VERSION 5.8 ;
BUSBITCHARS "[]" ;
DIVIDERCHAR "/" ;

VIA TPL1_C_0
  VIARULE TPL1_C ;
  CUTSIZE 0.17 0.17 ;
  LAYERS tap licon1 li1 ;
  CUTSPACING 0.17 0.17 ;
  ENCLOSURE 0.12 0.12 0.08 0.08 ;
  ROWCOL 1 1 ;
END TPL1_C_0

VIA TPL1_C_1
  VIARULE TPL1_C ;
  CUTSIZE 0.17 0.17 ;
  LAYERS tap licon1 li1 ;
  CUTSPACING 0.17 0.17 ;
  ENCLOSURE 0.12 0.12 0.08 0.08 ;
  ROWCOL 1 26 ;
END TPL1_C_1

VIA TPL1_C_2
  VIARULE TPL1_C ;
  CUTSIZE 0.17 0.17 ;
  LAYERS tap licon1 li1 ;
  CUTSPACING 0.17 0.17 ;
  ENCLOSURE 0.12 0.12 0.08 0.08 ;
  ROWCOL 1 24 ;
END TPL1_C_2

VIA PYL1_C_3
  VIARULE PYL1_C ;
  CUTSIZE 0.17 0.17 ;
  LAYERS poly licon1 li1 ;
  CUTSPACING 0.17 0.17 ;
  ENCLOSURE 0.08 0.08 0.08 0.08 ;
  ROWCOL 1 1 ;
END PYL1_C_3

VIA PYL1_C_4
  VIARULE PYL1_C ;
  CUTSIZE 0.17 0.17 ;
  LAYERS poly licon1 li1 ;
  CUTSPACING 0.17 0.17 ;
  ENCLOSURE 0.08 0.08 0.08 0.08 ;
  ROWCOL 1 6 ;
END PYL1_C_4

VIA PYL1_C_5
  VIARULE PYL1_C ;
  CUTSIZE 0.17 0.17 ;
  LAYERS poly licon1 li1 ;
  CUTSPACING 0.17 0.17 ;
  ENCLOSURE 0.08 0.08 0.08 0.08 ;
  ROWCOL 1 2 ;
END PYL1_C_5

VIA PYL1_C_6
  VIARULE PYL1_C ;
  CUTSIZE 0.17 0.17 ;
  LAYERS poly licon1 li1 ;
  CUTSPACING 0.17 0.17 ;
  ENCLOSURE 0.08 0.08 0.08 0.08 ;
  ROWCOL 1 22 ;
END PYL1_C_6

VIA PYL1_C_7
  VIARULE PYL1_C ;
  CUTSIZE 0.17 0.17 ;
  LAYERS poly licon1 li1 ;
  CUTSPACING 0.17 0.17 ;
  ENCLOSURE 0.08 0.08 0.08 0.08 ;
  ROWCOL 1 20 ;
END PYL1_C_7

VIA PYL1_C_8
  VIARULE PYL1_C ;
  CUTSIZE 0.17 0.17 ;
  LAYERS poly licon1 li1 ;
  CUTSPACING 0.17 0.17 ;
  ENCLOSURE 0.08 0.08 0.08 0.08 ;
  ROWCOL 1 23 ;
END PYL1_C_8

VIA PYL1_C_9
  VIARULE PYL1_C ;
  CUTSIZE 0.17 0.17 ;
  LAYERS poly licon1 li1 ;
  CUTSPACING 0.17 0.17 ;
  ENCLOSURE 0.08 0.08 0.08 0.08 ;
  ROWCOL 1 17 ;
END PYL1_C_9

VIA PYL1_C_10
  VIARULE PYL1_C ;
  CUTSIZE 0.17 0.17 ;
  LAYERS poly licon1 li1 ;
  CUTSPACING 0.17 0.17 ;
  ENCLOSURE 0.08 0.08 0.08 0.08 ;
  ROWCOL 1 8 ;
END PYL1_C_10

VIA PYL1_C_11
  VIARULE PYL1_C ;
  CUTSIZE 0.17 0.17 ;
  LAYERS poly licon1 li1 ;
  CUTSPACING 0.17 0.17 ;
  ENCLOSURE 0.08 0.08 0.08 0.08 ;
  ROWCOL 1 10 ;
END PYL1_C_11

VIA PYL1_C_12
  VIARULE PYL1_C ;
  CUTSIZE 0.17 0.17 ;
  LAYERS poly licon1 li1 ;
  CUTSPACING 0.17 0.17 ;
  ENCLOSURE 0.08 0.08 0.08 0.08 ;
  ROWCOL 1 1 ;
END PYL1_C_12

VIA PYL1_C_13
  VIARULE PYL1_C ;
  CUTSIZE 0.17 0.17 ;
  LAYERS poly licon1 li1 ;
  CUTSPACING 0.19 0.19 ;
  ENCLOSURE 0.08 0.08 0.08 0.08 ;
  ROWCOL 1 2 ;
END PYL1_C_13

VIA PYL1_C_14
  VIARULE PYL1_C ;
  CUTSIZE 0.17 0.17 ;
  LAYERS poly licon1 li1 ;
  CUTSPACING 0.17 0.17 ;
  ENCLOSURE 0.08 0.08 0.08 0.08 ;
  ROWCOL 1 14 ;
END PYL1_C_14

VIA PYL1_C_15
  VIARULE PYL1_C ;
  CUTSIZE 0.17 0.17 ;
  LAYERS poly licon1 li1 ;
  CUTSPACING 0.17 0.17 ;
  ENCLOSURE 0.08 0.08 0.08 0.08 ;
  ROWCOL 1 90 ;
END PYL1_C_15

VIA PYL1_C_16
  VIARULE PYL1_C ;
  CUTSIZE 0.17 0.17 ;
  LAYERS poly licon1 li1 ;
  CUTSPACING 0.17 0.17 ;
  ENCLOSURE 0.08 0.08 0.08 0.08 ;
  ROWCOL 1 4 ;
END PYL1_C_16

VIA PYL1_C_17
  VIARULE PYL1_C ;
  CUTSIZE 0.17 0.17 ;
  LAYERS poly licon1 li1 ;
  CUTSPACING 0.17 0.17 ;
  ENCLOSURE 0.08 0.08 0.08 0.08 ;
  ROWCOL 2 1 ;
END PYL1_C_17

VIA L1M1_C_18
  VIARULE L1M1_C ;
  CUTSIZE 0.17 0.17 ;
  LAYERS li1 mcon met1 ;
  CUTSPACING 0.19 0.19 ;
  ENCLOSURE 0 0 0.06 0.06 ;
  ROWCOL 1 1 ;
END L1M1_C_18

VIA L1M1_C_19
  VIARULE L1M1_C ;
  CUTSIZE 0.17 0.17 ;
  LAYERS li1 mcon met1 ;
  CUTSPACING 0.19 0.17 ;
  ENCLOSURE 0 0 0.06 0.06 ;
  ROWCOL 1 2 ;
END L1M1_C_19

VIA L1M1_C_20
  VIARULE L1M1_C ;
  CUTSIZE 0.17 0.17 ;
  LAYERS li1 mcon met1 ;
  CUTSPACING 0.19 0.17 ;
  ENCLOSURE 0 0 0.06 0.06 ;
  ROWCOL 1 18 ;
END L1M1_C_20

VIA L1M1_C_21
  VIARULE L1M1_C ;
  CUTSIZE 0.17 0.17 ;
  LAYERS li1 mcon met1 ;
  CUTSPACING 0.19 0.17 ;
  ENCLOSURE 0 0 0.06 0.06 ;
  ROWCOL 1 9 ;
END L1M1_C_21

VIA L1M1_C_22
  VIARULE L1M1_C ;
  CUTSIZE 0.17 0.17 ;
  LAYERS li1 mcon met1 ;
  CUTSPACING 0.19 0.17 ;
  ENCLOSURE 0 0 0.06 0.06 ;
  ROWCOL 1 3 ;
END L1M1_C_22

VIA L1M1_C_23
  VIARULE L1M1_C ;
  CUTSIZE 0.17 0.17 ;
  LAYERS li1 mcon met1 ;
  CUTSPACING 0.19 0.17 ;
  ENCLOSURE 0 0 0.06 0.06 ;
  ROWCOL 1 10 ;
END L1M1_C_23

VIA L1M1_C_24
  VIARULE L1M1_C ;
  CUTSIZE 0.17 0.17 ;
  LAYERS li1 mcon met1 ;
  CUTSPACING 0.19 0.19 ;
  ENCLOSURE 0 0 0.06 0.06 ;
  ROWCOL 22 1 ;
END L1M1_C_24

VIA L1M1_C_25
  VIARULE L1M1_C ;
  CUTSIZE 0.17 0.17 ;
  LAYERS li1 mcon met1 ;
  CUTSPACING 0.19 0.19 ;
  ENCLOSURE 0 0 0.06 0.06 ;
  ROWCOL 1 20 ;
END L1M1_C_25

VIA L1M1_C_26
  VIARULE L1M1_C ;
  CUTSIZE 0.17 0.17 ;
  LAYERS li1 mcon met1 ;
  CUTSPACING 0.19 0.19 ;
  ENCLOSURE 0 0 0.06 0.06 ;
  ROWCOL 1 8 ;
END L1M1_C_26

VIA L1M1_C_27
  VIARULE L1M1_C ;
  CUTSIZE 0.17 0.17 ;
  LAYERS li1 mcon met1 ;
  CUTSPACING 0.19 0.19 ;
  ENCLOSURE 0 0 0.06 0.06 ;
  ROWCOL 1 3 ;
END L1M1_C_27

VIA L1M1_C_28
  VIARULE L1M1_C ;
  CUTSIZE 0.17 0.17 ;
  LAYERS li1 mcon met1 ;
  CUTSPACING 0.19 0.19 ;
  ENCLOSURE 0 0 0.06 0.06 ;
  ROWCOL 1 12 ;
END L1M1_C_28

VIA L1M1_C_29
  VIARULE L1M1_C ;
  CUTSIZE 0.17 0.17 ;
  LAYERS li1 mcon met1 ;
  CUTSPACING 0.19 0.19 ;
  ENCLOSURE 0 0 0.06 0.06 ;
  ROWCOL 1 4 ;
END L1M1_C_29

VIA L1M1_C_30
  VIARULE L1M1_C ;
  CUTSIZE 0.17 0.17 ;
  LAYERS li1 mcon met1 ;
  CUTSPACING 0.19 0.19 ;
  ENCLOSURE 0 0 0.06 0.06 ;
  ROWCOL 1 85 ;
END L1M1_C_30

VIA L1M1_C_31
  VIARULE L1M1_C ;
  CUTSIZE 0.17 0.17 ;
  LAYERS li1 mcon met1 ;
  CUTSPACING 0.19 0.19 ;
  ENCLOSURE 0 0 0.06 0.06 ;
  ROWCOL 3 1 ;
END L1M1_C_31

VIA L1M1_C_32
  VIARULE L1M1_C ;
  CUTSIZE 0.17 0.17 ;
  LAYERS li1 mcon met1 ;
  CUTSPACING 0.19 0.19 ;
  ENCLOSURE 0 0 0.06 0.06 ;
  ROWCOL 1 2 ;
END L1M1_C_32

VIA L1M1_C_33
  VIARULE L1M1_C ;
  CUTSIZE 0.17 0.17 ;
  LAYERS li1 mcon met1 ;
  CUTSPACING 0.19 0.19 ;
  ENCLOSURE 0 0 0.06 0.06 ;
  ROWCOL 4 1 ;
END L1M1_C_33

VIA L1M1_C_34
  VIARULE L1M1_C ;
  CUTSIZE 0.17 0.17 ;
  LAYERS li1 mcon met1 ;
  CUTSPACING 0.19 0.19 ;
  ENCLOSURE 0 0 0.06 0.06 ;
  ROWCOL 2 2 ;
END L1M1_C_34

VIA L1M1_C_35
  VIARULE L1M1_C ;
  CUTSIZE 0.17 0.17 ;
  LAYERS li1 mcon met1 ;
  CUTSPACING 0.19 0.19 ;
  ENCLOSURE 0 0 0.06 0.06 ;
  ROWCOL 1 1 ;
END L1M1_C_35

VIA L1M1_C_36
  VIARULE L1M1_C ;
  CUTSIZE 0.17 0.17 ;
  LAYERS li1 mcon met1 ;
  CUTSPACING 0.19 0.19 ;
  ENCLOSURE 0 0 0.06 0.06 ;
  ROWCOL 2 1 ;
END L1M1_C_36

VIA L1M1_C_37
  VIARULE L1M1_C ;
  CUTSIZE 0.17 0.17 ;
  LAYERS li1 mcon met1 ;
  CUTSPACING 0.19 0.19 ;
  ENCLOSURE 0 0 0.06 0.06 ;
  ROWCOL 2 18 ;
END L1M1_C_37

VIA L1M1_C_38
  VIARULE L1M1_C ;
  CUTSIZE 0.17 0.17 ;
  LAYERS li1 mcon met1 ;
  CUTSPACING 0.19 0.19 ;
  ENCLOSURE 0 0 0.06 0.06 ;
  ROWCOL 1 7 ;
END L1M1_C_38

VIA M1M2_C_39
  VIARULE M1M2_C ;
  CUTSIZE 0.15 0.15 ;
  LAYERS met1 via met2 ;
  CUTSPACING 0.17 0.17 ;
  ENCLOSURE 0.085 0.085 0.085 0.085 ;
  ROWCOL 1 1 ;
END M1M2_C_39

VIA M1M2_C_40
  VIARULE M1M2_C ;
  CUTSIZE 0.15 0.15 ;
  LAYERS met1 via met2 ;
  CUTSPACING 0.17 0.17 ;
  ENCLOSURE 0.085 0.085 0.085 0.085 ;
  ROWCOL 2 3 ;
END M1M2_C_40

VIA M1M2_C_41
  VIARULE M1M2_C ;
  CUTSIZE 0.15 0.15 ;
  LAYERS met1 via met2 ;
  CUTSPACING 0.21 0.19 ;
  ENCLOSURE 0.085 0.085 0.085 0.085 ;
  ROWCOL 1 7 ;
END M1M2_C_41

VIA M1M2_C_42
  VIARULE M1M2_C ;
  CUTSIZE 0.15 0.15 ;
  LAYERS met1 via met2 ;
  CUTSPACING 0.21 0.19 ;
  ENCLOSURE 0.085 0.085 0.085 0.085 ;
  ROWCOL 1 10 ;
END M1M2_C_42

VIA M1M2_C_43
  VIARULE M1M2_C ;
  CUTSIZE 0.15 0.15 ;
  LAYERS met1 via met2 ;
  CUTSPACING 0.17 0.17 ;
  ENCLOSURE 0.085 0.085 0.085 0.085 ;
  ROWCOL 1 4 ;
END M1M2_C_43

VIA M1M2_C_44
  VIARULE M1M2_C ;
  CUTSIZE 0.15 0.15 ;
  LAYERS met1 via met2 ;
  CUTSPACING 0.17 0.17 ;
  ENCLOSURE 0.085 0.085 0.085 0.085 ;
  ROWCOL 10 1 ;
END M1M2_C_44

VIA M1M2_C_45
  VIARULE M1M2_C ;
  CUTSIZE 0.15 0.15 ;
  LAYERS met1 via met2 ;
  CUTSPACING 0.17 0.17 ;
  ENCLOSURE 0.085 0.085 0.085 0.085 ;
  ROWCOL 5 1 ;
END M1M2_C_45

VIA M1M2_C_46
  VIARULE M1M2_C ;
  CUTSIZE 0.15 0.15 ;
  LAYERS met1 via met2 ;
  CUTSPACING 0.17 0.17 ;
  ENCLOSURE 0.085 0.085 0.085 0.085 ;
  ROWCOL 14 1 ;
END M1M2_C_46

VIA M1M2_C_47
  VIARULE M1M2_C ;
  CUTSIZE 0.15 0.15 ;
  LAYERS met1 via met2 ;
  CUTSPACING 0.17 0.17 ;
  ENCLOSURE 0.085 0.085 0.085 0.085 ;
  ROWCOL 16 8 ;
END M1M2_C_47

VIA M1M2_C_48
  VIARULE M1M2_C ;
  CUTSIZE 0.15 0.15 ;
  LAYERS met1 via met2 ;
  CUTSPACING 0.17 0.17 ;
  ENCLOSURE 0.085 0.085 0.085 0.085 ;
  ROWCOL 3 5 ;
END M1M2_C_48

VIA M1M2_C_49
  VIARULE M1M2_C ;
  CUTSIZE 0.15 0.15 ;
  LAYERS met1 via met2 ;
  CUTSPACING 0.17 0.17 ;
  ENCLOSURE 0.085 0.085 0.085 0.085 ;
  ROWCOL 5 5 ;
END M1M2_C_49

VIA M1M2_C_50
  VIARULE M1M2_C ;
  CUTSIZE 0.15 0.15 ;
  LAYERS met1 via met2 ;
  CUTSPACING 0.17 0.17 ;
  ENCLOSURE 0.085 0.085 0.085 0.085 ;
  ROWCOL 20 1 ;
END M1M2_C_50

VIA M1M2_C_51
  VIARULE M1M2_C ;
  CUTSIZE 0.15 0.15 ;
  LAYERS met1 via met2 ;
  CUTSPACING 0.17 0.17 ;
  ENCLOSURE 0.085 0.085 0.085 0.085 ;
  ROWCOL 7 1 ;
END M1M2_C_51

VIA M1M2_C_52
  VIARULE M1M2_C ;
  CUTSIZE 0.15 0.15 ;
  LAYERS met1 via met2 ;
  CUTSPACING 0.17 0.17 ;
  ENCLOSURE 0.085 0.085 0.085 0.085 ;
  ROWCOL 9 3 ;
END M1M2_C_52

VIA M1M2_C_53
  VIARULE M1M2_C ;
  CUTSIZE 0.15 0.15 ;
  LAYERS met1 via met2 ;
  CUTSPACING 0.17 0.17 ;
  ENCLOSURE 0.085 0.085 0.085 0.085 ;
  ROWCOL 5 2 ;
END M1M2_C_53

VIA M1M2_C_54
  VIARULE M1M2_C ;
  CUTSIZE 0.15 0.15 ;
  LAYERS met1 via met2 ;
  CUTSPACING 0.17 0.17 ;
  ENCLOSURE 0.085 0.085 0.085 0.085 ;
  ROWCOL 1 8 ;
END M1M2_C_54

VIA M1M2_C_55
  VIARULE M1M2_C ;
  CUTSIZE 0.15 0.15 ;
  LAYERS met1 via met2 ;
  CUTSPACING 0.17 0.17 ;
  ENCLOSURE 0.085 0.085 0.085 0.085 ;
  ROWCOL 8 1 ;
END M1M2_C_55

VIA M1M2_C_56
  VIARULE M1M2_C ;
  CUTSIZE 0.15 0.15 ;
  LAYERS met1 via met2 ;
  CUTSPACING 0.17 0.17 ;
  ENCLOSURE 0.085 0.085 0.085 0.085 ;
  ROWCOL 7 3 ;
END M1M2_C_56

VIA M1M2_C_57
  VIARULE M1M2_C ;
  CUTSIZE 0.15 0.15 ;
  LAYERS met1 via met2 ;
  CUTSPACING 0.21 0.21 ;
  ENCLOSURE 0.085 0.085 0.085 0.085 ;
  ROWCOL 2 1 ;
END M1M2_C_57

VIA M1M2_C_58
  VIARULE M1M2_C ;
  CUTSIZE 0.15 0.15 ;
  LAYERS met1 via met2 ;
  CUTSPACING 0.17 0.17 ;
  ENCLOSURE 0.085 0.085 0.085 0.085 ;
  ROWCOL 3 3 ;
END M1M2_C_58

VIA M1M2_C_59
  VIARULE M1M2_C ;
  CUTSIZE 0.15 0.15 ;
  LAYERS met1 via met2 ;
  CUTSPACING 0.17 0.17 ;
  ENCLOSURE 0.085 0.085 0.085 0.085 ;
  ROWCOL 5 3 ;
END M1M2_C_59

VIA M1M2_C_60
  VIARULE M1M2_C ;
  CUTSIZE 0.15 0.15 ;
  LAYERS met1 via met2 ;
  CUTSPACING 0.17 0.17 ;
  ENCLOSURE 0.085 0.085 0.085 0.085 ;
  ROWCOL 5 8 ;
END M1M2_C_60

VIA M1M2_C_61
  VIARULE M1M2_C ;
  CUTSIZE 0.15 0.15 ;
  LAYERS met1 via met2 ;
  CUTSPACING 0.17 0.17 ;
  ENCLOSURE 0.085 0.085 0.085 0.085 ;
  ROWCOL 14 7 ;
END M1M2_C_61

VIA M1M2_C_62
  VIARULE M1M2_C ;
  CUTSIZE 0.15 0.15 ;
  LAYERS met1 via met2 ;
  CUTSPACING 0.17 0.17 ;
  ENCLOSURE 0.085 0.085 0.085 0.085 ;
  ROWCOL 19 7 ;
END M1M2_C_62

VIA M1M2_C_63
  VIARULE M1M2_C ;
  CUTSIZE 0.15 0.15 ;
  LAYERS met1 via met2 ;
  CUTSPACING 0.17 0.17 ;
  ENCLOSURE 0.085 0.085 0.085 0.085 ;
  ROWCOL 20 7 ;
END M1M2_C_63

VIA M1M2_C_64
  VIARULE M1M2_C ;
  CUTSIZE 0.15 0.15 ;
  LAYERS met1 via met2 ;
  CUTSPACING 0.17 0.17 ;
  ENCLOSURE 0.085 0.085 0.085 0.085 ;
  ROWCOL 15 10 ;
END M1M2_C_64

VIA M1M2_C_65
  VIARULE M1M2_C ;
  CUTSIZE 0.15 0.15 ;
  LAYERS met1 via met2 ;
  CUTSPACING 0.17 0.17 ;
  ENCLOSURE 0.085 0.085 0.085 0.085 ;
  ROWCOL 4 1 ;
END M1M2_C_65

VIA M1M2_C_66
  VIARULE M1M2_C ;
  CUTSIZE 0.15 0.15 ;
  LAYERS met1 via met2 ;
  CUTSPACING 0.17 0.17 ;
  ENCLOSURE 0.085 0.085 0.085 0.085 ;
  ROWCOL 1 3 ;
END M1M2_C_66

VIA M1M2_C_67
  VIARULE M1M2_C ;
  CUTSIZE 0.15 0.15 ;
  LAYERS met1 via met2 ;
  CUTSPACING 0.17 0.17 ;
  ENCLOSURE 0.085 0.085 0.085 0.085 ;
  ROWCOL 3 2 ;
END M1M2_C_67

VIA M1M2_C_68
  VIARULE M1M2_C ;
  CUTSIZE 0.15 0.15 ;
  LAYERS met1 via met2 ;
  CUTSPACING 0.17 0.17 ;
  ENCLOSURE 0.085 0.085 0.085 0.085 ;
  ROWCOL 6 8 ;
END M1M2_C_68

VIA M1M2_C_69
  VIARULE M1M2_C ;
  CUTSIZE 0.15 0.15 ;
  LAYERS met1 via met2 ;
  CUTSPACING 0.17 0.17 ;
  ENCLOSURE 0.085 0.085 0.085 0.085 ;
  ROWCOL 2 2 ;
END M1M2_C_69

VIA M1M2_C_70
  VIARULE M1M2_C ;
  CUTSIZE 0.15 0.15 ;
  LAYERS met1 via met2 ;
  CUTSPACING 0.17 0.17 ;
  ENCLOSURE 0.085 0.085 0.085 0.085 ;
  ROWCOL 3 1 ;
END M1M2_C_70

VIA M1M2_C_71
  VIARULE M1M2_C ;
  CUTSIZE 0.15 0.15 ;
  LAYERS met1 via met2 ;
  CUTSPACING 0.17 0.17 ;
  ENCLOSURE 0.085 0.085 0.085 0.085 ;
  ROWCOL 6 1 ;
END M1M2_C_71

VIA M1M2_C_72
  VIARULE M1M2_C ;
  CUTSIZE 0.15 0.15 ;
  LAYERS met1 via met2 ;
  CUTSPACING 0.17 0.17 ;
  ENCLOSURE 0.085 0.085 0.085 0.085 ;
  ROWCOL 1 6 ;
END M1M2_C_72

VIA M1M2_C_73
  VIARULE M1M2_C ;
  CUTSIZE 0.15 0.15 ;
  LAYERS met1 via met2 ;
  CUTSPACING 0.17 0.17 ;
  ENCLOSURE 0.085 0.085 0.085 0.085 ;
  ROWCOL 1 2 ;
END M1M2_C_73

VIA M1M2_C_74
  VIARULE M1M2_C ;
  CUTSIZE 0.15 0.15 ;
  LAYERS met1 via met2 ;
  CUTSPACING 0.17 0.17 ;
  ENCLOSURE 0.085 0.085 0.085 0.085 ;
  ROWCOL 2 1 ;
END M1M2_C_74

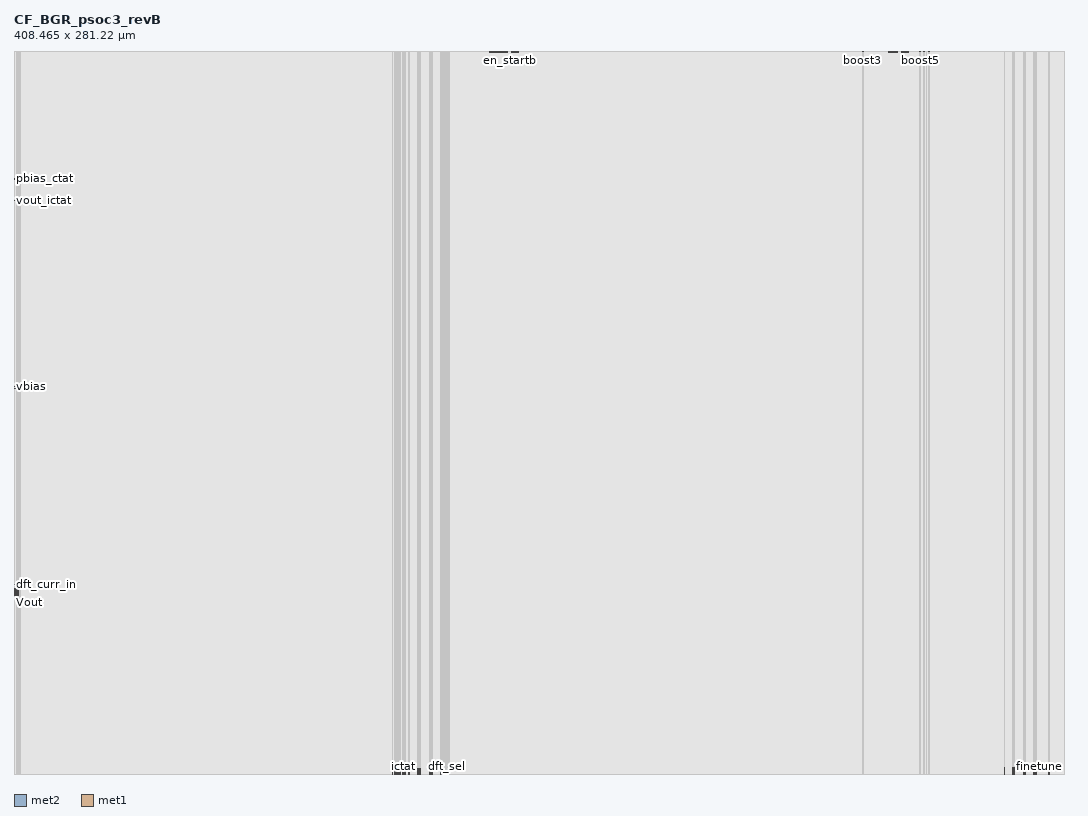
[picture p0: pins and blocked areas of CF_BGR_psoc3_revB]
MACRO CF_BGR_psoc3_revB
  ORIGIN 0 0 ;
  FOREIGN CF_BGR_psoc3_revB 0 0 ;
  SIZE 408.465 BY 281.22 ;
  PIN CurrAbsTrim[5]
    DIRECTION INPUT ;
    USE SIGNAL ;
    PORT
      LAYER met2 ;
        RECT 166.425 0 166.565 2.055 ;
    END
  END CurrAbsTrim[5]
  PIN finetune
    DIRECTION INPUT ;
    USE SIGNAL ;
    PORT
      LAYER met2 ;
        RECT 402.5 0 402.64 1.22 ;
    END
  END finetune
  PIN boost4
    DIRECTION OUTPUT ;
    USE SIGNAL ;
    PORT
      LAYER met2 ;
        RECT 355.79 281.025 356.11 281.22 ;
    END
  END boost4
  PIN boost7
    DIRECTION OUTPUT ;
    USE SIGNAL ;
    PORT
      LAYER met2 ;
        RECT 354.845 281.025 355.165 281.22 ;
    END
  END boost7
  PIN boost6
    DIRECTION OUTPUT ;
    USE SIGNAL ;
    PORT
      LAYER met2 ;
        RECT 353.765 281.035 354.085 281.22 ;
    END
  END boost6
  PIN boost5
    DIRECTION OUTPUT ;
    USE SIGNAL ;
    PORT
      LAYER met2 ;
        RECT 352.36 281.045 352.68 281.22 ;
    END
  END boost5
  PIN en_startb
    DIRECTION INPUT ;
    USE SIGNAL ;
    PORT
      LAYER met1 ;
        RECT 192.72 281.035 192.86 281.22 ;
    END
  END en_startb
  PIN trimCurr[5]
    DIRECTION INPUT ;
    USE SIGNAL ;
    PORT
      LAYER met2 ;
        RECT 153.295 0 153.435 2.055 ;
    END
  END trimCurr[5]
  PIN trimCurr[4]
    DIRECTION INPUT ;
    USE SIGNAL ;
    PORT
      LAYER met2 ;
        RECT 157.055 0 157.195 2.055 ;
    END
  END trimCurr[4]
  PIN trimCurr[3]
    DIRECTION INPUT ;
    USE SIGNAL ;
    PORT
      LAYER met2 ;
        RECT 157.425 0 157.565 2.055 ;
    END
  END trimCurr[3]
  PIN trimCurr[2]
    DIRECTION INPUT ;
    USE SIGNAL ;
    PORT
      LAYER met2 ;
        RECT 157.795 0 157.935 2.055 ;
    END
  END trimCurr[2]
  PIN trimCurr[0]
    DIRECTION INPUT ;
    USE SIGNAL ;
    PORT
      LAYER met2 ;
        RECT 158.165 0 158.305 2.055 ;
    END
  END trimCurr[0]
  PIN trimCurr[1]
    DIRECTION INPUT ;
    USE SIGNAL ;
    PORT
      LAYER met2 ;
        RECT 161.555 0 161.695 2.055 ;
    END
  END trimCurr[1]
  PIN CurrAbsTrim[0]
    DIRECTION INPUT ;
    USE SIGNAL ;
    PORT
      LAYER met2 ;
        RECT 153.665 0 153.805 2.055 ;
    END
  END CurrAbsTrim[0]
  PIN CurrAbsTrim[1]
    DIRECTION INPUT ;
    USE SIGNAL ;
    PORT
      LAYER met2 ;
        RECT 161.925 0 162.065 2.055 ;
    END
  END CurrAbsTrim[1]
  PIN CurrAbsTrim[2]
    DIRECTION INPUT ;
    USE SIGNAL ;
    PORT
      LAYER met2 ;
        RECT 162.295 0 162.435 2.055 ;
    END
  END CurrAbsTrim[2]
  PIN CurrAbsTrim[3]
    DIRECTION INPUT ;
    USE SIGNAL ;
    PORT
      LAYER met2 ;
        RECT 162.665 0 162.805 2.055 ;
    END
  END CurrAbsTrim[3]
  PIN CurrAbsTrim[4]
    DIRECTION INPUT ;
    USE SIGNAL ;
    PORT
      LAYER met2 ;
        RECT 166.055 0 166.195 2.055 ;
    END
  END CurrAbsTrim[4]
  PIN mux2sel
    DIRECTION INPUT ;
    USE SIGNAL ;
    PORT
      LAYER met2 ;
        RECT 167.16 0 167.3 1.035 ;
    END
  END mux2sel
  PIN mux1sel[0]
    DIRECTION INPUT ;
    USE SIGNAL ;
    PORT
      LAYER met2 ;
        RECT 167.53 0 167.67 1.035 ;
    END
  END mux1sel[0]
  PIN mux1sel[1]
    DIRECTION INPUT ;
    USE SIGNAL ;
    PORT
      LAYER met2 ;
        RECT 167.9 0 168.04 1.035 ;
    END
  END mux1sel[1]
  PIN dft_sel
    DIRECTION INPUT ;
    USE SIGNAL ;
    PORT
      LAYER met2 ;
        RECT 168.27 0 168.41 1.035 ;
    END
  END dft_sel
  PIN pd_ibg
    DIRECTION INPUT ;
    USE SIGNAL ;
    PORT
      LAYER met2 ;
        RECT 168.65 0 168.79 1.035 ;
    END
  END pd_ibg
  PIN pd
    DIRECTION INPUT ;
    USE SIGNAL ;
    PORT
      LAYER met2 ;
        RECT 169.095 0 169.235 1.035 ;
    END
  END pd
  PIN trimTC[6]
    DIRECTION INPUT ;
    USE SIGNAL ;
    PORT
      LAYER met2 ;
        RECT 385.145 0 385.285 2.375 ;
    END
  END trimTC[6]
  PIN trimTC[5]
    DIRECTION INPUT ;
    USE SIGNAL ;
    PORT
      LAYER met2 ;
        RECT 388.535 0 388.675 2.375 ;
    END
  END trimTC[5]
  PIN trimTC[4]
    DIRECTION INPUT ;
    USE SIGNAL ;
    PORT
      LAYER met2 ;
        RECT 389.18 0 389.32 2.375 ;
    END
  END trimTC[4]
  PIN trimTC[3]
    DIRECTION INPUT ;
    USE SIGNAL ;
    PORT
      LAYER met2 ;
        RECT 392.57 0 392.71 1.77 ;
    END
  END trimTC[3]
  PIN trimTC[2]
    DIRECTION INPUT ;
    USE SIGNAL ;
    PORT
      LAYER met2 ;
        RECT 393.27 0 393.41 1.77 ;
    END
  END trimTC[2]
  PIN trimTC[0]
    DIRECTION INPUT ;
    USE SIGNAL ;
    PORT
      LAYER met2 ;
        RECT 396.66 0 396.8 1.465 ;
    END
  END trimTC[0]
  PIN trimTC[1]
    DIRECTION INPUT ;
    USE SIGNAL ;
    PORT
      LAYER met2 ;
        RECT 397.535 0 397.675 1.22 ;
    END
  END trimTC[1]
  PIN inl_ctrl[0]
    DIRECTION INPUT ;
    USE SIGNAL ;
    PORT
      LAYER met2 ;
        RECT 150.955 0 151.095 2.055 ;
    END
  END inl_ctrl[0]
  PIN inl_ctrl[1]
    DIRECTION INPUT ;
    USE SIGNAL ;
    PORT
      LAYER met2 ;
        RECT 150.355 0 150.495 2.055 ;
    END
  END inl_ctrl[1]
  PIN vbias_cascode
    DIRECTION OUTPUT ;
    USE SIGNAL ;
    PORT
      LAYER met2 ;
        RECT 0 150 2.075 150.14 ;
    END
  END vbias_cascode
  PIN vbias
    DIRECTION OUTPUT ;
    USE SIGNAL ;
    PORT
      LAYER met2 ;
        RECT 0 150.78 2.075 150.92 ;
    END
  END vbias
  PIN boost3
    DIRECTION OUTPUT ;
    USE SIGNAL ;
    PORT
      LAYER met2 ;
        RECT 330.055 281.05 330.375 281.22 ;
    END
  END boost3
  PIN dft_curr_in
    DIRECTION INPUT ;
    USE SIGNAL ;
    PORT
      LAYER met2 ;
        RECT 0 73.67 1.495 73.81 ;
    END
  END dft_curr_in
  PIN vb2_fast
    DIRECTION INPUT ;
    USE SIGNAL ;
    PORT
      LAYER met1 ;
        RECT 198.215 281.01 198.395 281.22 ;
    END
  END vb2_fast
  PIN Vout
    DIRECTION OUTPUT ;
    USE SIGNAL ;
    PORT
      LAYER met2 ;
        RECT 0 69.61 1.75 69.75 ;
    END
  END Vout
  PIN ibg_3uA
    DIRECTION OUTPUT ;
    USE SIGNAL ;
    PORT
      LAYER met2 ;
        RECT 0 70.11 1.75 70.25 ;
    END
  END ibg_3uA
  PIN ibg_2p375uA
    DIRECTION OUTPUT ;
    USE SIGNAL ;
    PORT
      LAYER met2 ;
        RECT 0 70.55 1.75 70.69 ;
    END
  END ibg_2p375uA
  PIN mux1out
    DIRECTION OUTPUT ;
    USE SIGNAL ;
    PORT
      LAYER met2 ;
        RECT 0 71.08 1.75 71.22 ;
    END
  END mux1out
  PIN mux2out
    DIRECTION OUTPUT ;
    USE SIGNAL ;
    PORT
      LAYER met2 ;
        RECT 0 71.875 1.75 72.015 ;
    END
  END mux2out
  PIN ictat
    DIRECTION OUTPUT ;
    USE SIGNAL ;
    PORT
      LAYER met2 ;
        RECT 151.615 0 151.755 1.035 ;
    END
  END ictat
  PIN iptat
    DIRECTION OUTPUT ;
    USE SIGNAL ;
    PORT
      LAYER met2 ;
        RECT 152.22 0 152.36 1.035 ;
    END
  END iptat
  PIN inl_ctrl[6]
    DIRECTION INPUT ;
    USE SIGNAL ;
    PORT
      LAYER met2 ;
        RECT 147.285 0 147.425 1.945 ;
    END
  END inl_ctrl[6]
  PIN inl_ctrl[5]
    DIRECTION INPUT ;
    USE SIGNAL ;
    PORT
      LAYER met2 ;
        RECT 147.9 0 148.04 1.935 ;
    END
  END inl_ctrl[5]
  PIN vpb
    DIRECTION INPUT ;
    USE SIGNAL ;
    PORT
      LAYER met1 ;
        RECT 184.955 280.82 192.08 281.22 ;
    END
  END vpb
  PIN vgnd
    DIRECTION INPUT ;
    USE SIGNAL ;
    PORT
      LAYER met1 ;
        RECT 340.21 280.82 343.78 281.22 ;
    END
  END vgnd
  PIN vnb
    DIRECTION INPUT ;
    USE SIGNAL ;
    PORT
      LAYER met1 ;
        RECT 345.205 280.82 347.975 281.22 ;
    END
  END vnb
  PIN vpwr
    DIRECTION INPUT ;
    USE SIGNAL ;
    PORT
      LAYER met1 ;
        RECT 193.455 280.82 196.235 281.22 ;
    END
  END vpwr
  PIN inl_ctrl[3]
    DIRECTION INPUT ;
    USE SIGNAL ;
    PORT
      LAYER met2 ;
        RECT 149.12 0 149.26 1.935 ;
    END
  END inl_ctrl[3]
  PIN inl_ctrl[2]
    DIRECTION INPUT ;
    USE SIGNAL ;
    PORT
      LAYER met2 ;
        RECT 149.725 0 149.865 1.945 ;
    END
  END inl_ctrl[2]
  PIN pbias_ctat
    DIRECTION OUTPUT ;
    USE SIGNAL ;
    PORT
      LAYER met2 ;
        RECT 0 231.46 2.49 231.6 ;
    END
  END pbias_ctat
  PIN vout_ictat
    DIRECTION OUTPUT ;
    USE SIGNAL ;
    PORT
      LAYER met2 ;
        RECT 0 223.03 1.015 223.17 ;
    END
  END vout_ictat
  PIN inl_ctrl[4]
    DIRECTION INPUT ;
    USE SIGNAL ;
    PORT
      LAYER met2 ;
        RECT 148.505 0 148.645 1.945 ;
    END
  END inl_ctrl[4]
  OBS
    LAYER li1 ;
      RECT 0 0 408.465 281.22 ;
    LAYER met1 ;
      RECT 0 0 184.955 281.22 ;
      RECT 184.955 0 192.08 280.82 ;
      RECT 192.08 0 192.72 281.22 ;
      RECT 192.72 0 192.86 281.035 ;
      RECT 192.86 0 193.455 281.22 ;
      RECT 193.455 0 196.235 280.82 ;
      RECT 196.235 0 198.215 281.22 ;
      RECT 198.215 0 198.395 281.01 ;
      RECT 198.395 0 340.21 281.22 ;
      RECT 340.21 0 343.78 280.82 ;
      RECT 343.78 0 345.205 281.22 ;
      RECT 345.205 0 347.975 280.82 ;
      RECT 347.975 0 408.465 281.22 ;
    LAYER met2 ;
      RECT 0 0 1.015 69.61 ;
      RECT 0 69.75 1.015 70.11 ;
      RECT 0 70.25 1.015 70.55 ;
      RECT 0 70.69 1.015 71.08 ;
      RECT 0 71.22 1.015 71.875 ;
      RECT 0 72.015 1.015 73.67 ;
      RECT 0 73.81 1.015 150 ;
      RECT 0 150.14 1.015 150.78 ;
      RECT 0 150.92 1.015 223.03 ;
      RECT 0 223.17 1.015 231.46 ;
      RECT 0 231.6 1.015 281.22 ;
      RECT 1.015 0 1.495 69.61 ;
      RECT 1.015 69.75 1.495 70.11 ;
      RECT 1.015 70.25 1.495 70.55 ;
      RECT 1.015 70.69 1.495 71.08 ;
      RECT 1.015 71.22 1.495 71.875 ;
      RECT 1.015 72.015 1.495 73.67 ;
      RECT 1.015 73.81 1.495 150 ;
      RECT 1.015 150.14 1.495 150.78 ;
      RECT 1.015 150.92 1.495 231.46 ;
      RECT 1.015 231.6 1.495 281.22 ;
      RECT 1.495 0 1.75 69.61 ;
      RECT 1.495 69.75 1.75 70.11 ;
      RECT 1.495 70.25 1.75 70.55 ;
      RECT 1.495 70.69 1.75 71.08 ;
      RECT 1.495 71.22 1.75 71.875 ;
      RECT 1.495 72.015 1.75 150 ;
      RECT 1.495 150.14 1.75 150.78 ;
      RECT 1.495 150.92 1.75 231.46 ;
      RECT 1.495 231.6 1.75 281.22 ;
      RECT 1.75 0 2.075 150 ;
      RECT 1.75 150.14 2.075 150.78 ;
      RECT 1.75 150.92 2.075 231.46 ;
      RECT 1.75 231.6 2.075 281.22 ;
      RECT 2.075 0 2.49 231.46 ;
      RECT 2.075 231.6 2.49 281.22 ;
      RECT 2.49 0 147.285 281.22 ;
      RECT 147.285 1.945 147.425 281.22 ;
      RECT 147.425 0 147.9 281.22 ;
      RECT 147.9 1.935 148.04 281.22 ;
      RECT 148.04 0 148.505 281.22 ;
      RECT 148.505 1.945 148.645 281.22 ;
      RECT 148.645 0 149.12 281.22 ;
      RECT 149.12 1.935 149.26 281.22 ;
      RECT 149.26 0 149.725 281.22 ;
      RECT 149.725 1.945 149.865 281.22 ;
      RECT 149.865 0 150.355 281.22 ;
      RECT 150.355 2.055 150.495 281.22 ;
      RECT 150.495 0 150.955 281.22 ;
      RECT 150.955 2.055 151.095 281.22 ;
      RECT 151.095 0 151.615 281.22 ;
      RECT 151.615 1.035 151.755 281.22 ;
      RECT 151.755 0 152.22 281.22 ;
      RECT 152.22 1.035 152.36 281.22 ;
      RECT 152.36 0 153.295 281.22 ;
      RECT 153.295 2.055 153.435 281.22 ;
      RECT 153.435 0 153.665 281.22 ;
      RECT 153.665 2.055 153.805 281.22 ;
      RECT 153.805 0 157.055 281.22 ;
      RECT 157.055 2.055 157.195 281.22 ;
      RECT 157.195 0 157.425 281.22 ;
      RECT 157.425 2.055 157.565 281.22 ;
      RECT 157.565 0 157.795 281.22 ;
      RECT 157.795 2.055 157.935 281.22 ;
      RECT 157.935 0 158.165 281.22 ;
      RECT 158.165 2.055 158.305 281.22 ;
      RECT 158.305 0 161.555 281.22 ;
      RECT 161.555 2.055 161.695 281.22 ;
      RECT 161.695 0 161.925 281.22 ;
      RECT 161.925 2.055 162.065 281.22 ;
      RECT 162.065 0 162.295 281.22 ;
      RECT 162.295 2.055 162.435 281.22 ;
      RECT 162.435 0 162.665 281.22 ;
      RECT 162.665 2.055 162.805 281.22 ;
      RECT 162.805 0 166.055 281.22 ;
      RECT 166.055 2.055 166.195 281.22 ;
      RECT 166.195 0 166.425 281.22 ;
      RECT 166.425 2.055 166.565 281.22 ;
      RECT 166.565 0 167.16 281.22 ;
      RECT 167.16 1.035 167.3 281.22 ;
      RECT 167.3 0 167.53 281.22 ;
      RECT 167.53 1.035 167.67 281.22 ;
      RECT 167.67 0 167.9 281.22 ;
      RECT 167.9 1.035 168.04 281.22 ;
      RECT 168.04 0 168.27 281.22 ;
      RECT 168.27 1.035 168.41 281.22 ;
      RECT 168.41 0 168.65 281.22 ;
      RECT 168.65 1.035 168.79 281.22 ;
      RECT 168.79 0 169.095 281.22 ;
      RECT 169.095 1.035 169.235 281.22 ;
      RECT 169.235 0 330.055 281.22 ;
      RECT 330.055 0 330.375 281.05 ;
      RECT 330.375 0 352.36 281.22 ;
      RECT 352.36 0 352.68 281.045 ;
      RECT 352.68 0 353.765 281.22 ;
      RECT 353.765 0 354.085 281.035 ;
      RECT 354.085 0 354.845 281.22 ;
      RECT 354.845 0 355.165 281.025 ;
      RECT 355.165 0 355.79 281.22 ;
      RECT 355.79 0 356.11 281.025 ;
      RECT 356.11 0 385.145 281.22 ;
      RECT 385.145 2.375 385.285 281.22 ;
      RECT 385.285 0 388.535 281.22 ;
      RECT 388.535 2.375 388.675 281.22 ;
      RECT 388.675 0 389.18 281.22 ;
      RECT 389.18 2.375 389.32 281.22 ;
      RECT 389.32 0 392.57 281.22 ;
      RECT 392.57 1.77 392.71 281.22 ;
      RECT 392.71 0 393.27 281.22 ;
      RECT 393.27 1.77 393.41 281.22 ;
      RECT 393.41 0 396.66 281.22 ;
      RECT 396.66 1.465 396.8 281.22 ;
      RECT 396.8 0 397.535 281.22 ;
      RECT 397.535 1.22 397.675 281.22 ;
      RECT 397.675 0 402.5 281.22 ;
      RECT 402.5 1.22 402.64 281.22 ;
      RECT 402.64 0 408.465 281.22 ;
  END
END CF_BGR_psoc3_revB

END LIBRARY
